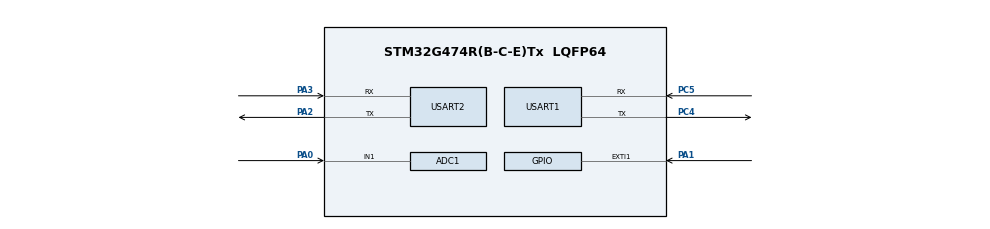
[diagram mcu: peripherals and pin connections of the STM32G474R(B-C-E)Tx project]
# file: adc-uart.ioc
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ADC1.AWD1ITMode=ENABLE
ADC1.Channel-0\#ChannelRegularConversion=ADC_CHANNEL_1
ADC1.EnableAnalogWatchDog1=true
ADC1.ExternalTrigConv=ADC_EXTERNALTRIG_T3_TRGO
ADC1.NbrOfConversionFlag=1
ADC1.OffsetNumber-0\#ChannelRegularConversion=ADC_OFFSET_NONE
ADC1.Rank-0\#ChannelRegularConversion=1
ADC1.SamplingTime-0\#ChannelRegularConversion=ADC_SAMPLETIME_2CYCLES_5
ADC1.WatchdogChannel=ADC_CHANNEL_1
ADC1.master=1
Dma.ADC1.2.Direction=DMA_PERIPH_TO_MEMORY
Dma.ADC1.2.EventEnable=DISABLE
Dma.ADC1.2.Instance=DMA1_Channel3
Dma.ADC1.2.MemDataAlignment=DMA_MDATAALIGN_HALFWORD
Dma.ADC1.2.MemInc=DMA_MINC_ENABLE
Dma.ADC1.2.Mode=DMA_NORMAL
Dma.ADC1.2.PeriphDataAlignment=DMA_PDATAALIGN_HALFWORD
Dma.ADC1.2.PeriphInc=DMA_PINC_DISABLE
Dma.ADC1.2.Polarity=HAL_DMAMUX_REQ_GEN_RISING
Dma.ADC1.2.Priority=DMA_PRIORITY_HIGH
Dma.ADC1.2.RequestNumber=1
Dma.ADC1.2.SignalID=NONE
Dma.ADC1.2.SyncEnable=DISABLE
Dma.ADC1.2.SyncPolarity=HAL_DMAMUX_SYNC_NO_EVENT
Dma.ADC1.2.SyncRequestNumber=1
Dma.ADC1.2.SyncSignalID=NONE
Dma.Request0=USART1_TX
Dma.Request1=USART2_TX
Dma.Request2=ADC1
Dma.Request3=USART1_RX
Dma.Request4=USART2_RX
Dma.USART1_RX.3.Direction=DMA_PERIPH_TO_MEMORY
Dma.USART1_RX.3.EventEnable=DISABLE
Dma.USART1_RX.3.Instance=DMA1_Channel4
Dma.USART1_RX.3.MemDataAlignment=DMA_MDATAALIGN_BYTE
Dma.USART1_RX.3.MemInc=DMA_MINC_ENABLE
Dma.USART1_RX.3.Mode=DMA_NORMAL
Dma.USART1_RX.3.PeriphDataAlignment=DMA_PDATAALIGN_BYTE
Dma.USART1_RX.3.PeriphInc=DMA_PINC_DISABLE
Dma.USART1_RX.3.Polarity=HAL_DMAMUX_REQ_GEN_RISING
Dma.USART1_RX.3.Priority=DMA_PRIORITY_LOW
Dma.USART1_RX.3.RequestNumber=1
Dma.USART1_RX.3.SignalID=NONE
Dma.USART1_RX.3.SyncEnable=DISABLE
Dma.USART1_RX.3.SyncPolarity=HAL_DMAMUX_SYNC_NO_EVENT
Dma.USART1_RX.3.SyncRequestNumber=1
Dma.USART1_RX.3.SyncSignalID=NONE
Dma.USART1_TX.0.Direction=DMA_MEMORY_TO_PERIPH
Dma.USART1_TX.0.EventEnable=DISABLE
Dma.USART1_TX.0.Instance=DMA1_Channel1
Dma.USART1_TX.0.MemDataAlignment=DMA_MDATAALIGN_BYTE
Dma.USART1_TX.0.MemInc=DMA_MINC_ENABLE
Dma.USART1_TX.0.Mode=DMA_NORMAL
Dma.USART1_TX.0.PeriphDataAlignment=DMA_PDATAALIGN_BYTE
Dma.USART1_TX.0.PeriphInc=DMA_PINC_DISABLE
Dma.USART1_TX.0.Polarity=HAL_DMAMUX_REQ_GEN_RISING
Dma.USART1_TX.0.Priority=DMA_PRIORITY_LOW
Dma.USART1_TX.0.RequestNumber=1
Dma.USART1_TX.0.SignalID=NONE
Dma.USART1_TX.0.SyncEnable=DISABLE
Dma.USART1_TX.0.SyncPolarity=HAL_DMAMUX_SYNC_NO_EVENT
Dma.USART1_TX.0.SyncRequestNumber=1
Dma.USART1_TX.0.SyncSignalID=NONE
Dma.USART2_RX.4.Direction=DMA_PERIPH_TO_MEMORY
Dma.USART2_RX.4.EventEnable=DISABLE
Dma.USART2_RX.4.Instance=DMA1_Channel5
Dma.USART2_RX.4.MemDataAlignment=DMA_MDATAALIGN_BYTE
Dma.USART2_RX.4.MemInc=DMA_MINC_ENABLE
Dma.USART2_RX.4.Mode=DMA_NORMAL
Dma.USART2_RX.4.PeriphDataAlignment=DMA_PDATAALIGN_BYTE
Dma.USART2_RX.4.PeriphInc=DMA_PINC_DISABLE
Dma.USART2_RX.4.Polarity=HAL_DMAMUX_REQ_GEN_RISING
Dma.USART2_RX.4.Priority=DMA_PRIORITY_LOW
Dma.USART2_RX.4.RequestNumber=1
Dma.USART2_RX.4.SignalID=NONE
Dma.USART2_RX.4.SyncEnable=DISABLE
Dma.USART2_RX.4.SyncPolarity=HAL_DMAMUX_SYNC_NO_EVENT
Dma.USART2_RX.4.SyncRequestNumber=1
Dma.USART2_RX.4.SyncSignalID=NONE
Dma.USART2_TX.1.Direction=DMA_MEMORY_TO_PERIPH
Dma.USART2_TX.1.EventEnable=DISABLE
Dma.USART2_TX.1.Instance=DMA1_Channel2
Dma.USART2_TX.1.MemDataAlignment=DMA_MDATAALIGN_BYTE
Dma.USART2_TX.1.MemInc=DMA_MINC_ENABLE
Dma.USART2_TX.1.Mode=DMA_NORMAL
Dma.USART2_TX.1.PeriphDataAlignment=DMA_PDATAALIGN_BYTE
Dma.USART2_TX.1.PeriphInc=DMA_PINC_DISABLE
Dma.USART2_TX.1.Polarity=HAL_DMAMUX_REQ_GEN_RISING
Dma.USART2_TX.1.Priority=DMA_PRIORITY_LOW
Dma.USART2_TX.1.RequestNumber=1
Dma.USART2_TX.1.SignalID=NONE
Dma.USART2_TX.1.SyncEnable=DISABLE
Dma.USART2_TX.1.SyncPolarity=HAL_DMAMUX_SYNC_NO_EVENT
Dma.USART2_TX.1.SyncRequestNumber=1
Dma.USART2_TX.1.SyncSignalID=NONE
Mcu.Family=STM32G4
Mcu.Name=STM32G474R(B-C-E)Tx
Mcu.Package=LQFP64
NVIC.ADC1_2_IRQn=true\:0\:0\:false\:false\:true\:true\:true\:true
NVIC.DMA1_Channel1_IRQn=true\:0\:0\:false\:false\:true\:false\:true\:true
NVIC.DMA1_Channel2_IRQn=true\:0\:0\:false\:false\:true\:false\:true\:true
NVIC.DMA1_Channel3_IRQn=true\:0\:0\:false\:false\:true\:false\:true\:true
NVIC.DMA1_Channel4_IRQn=true\:0\:0\:false\:false\:true\:false\:true\:true
NVIC.DMA1_Channel5_IRQn=true\:0\:0\:false\:false\:true\:false\:true\:true
NVIC.EXTI1_IRQn=true\:0\:0\:false\:false\:true\:true\:true\:true
NVIC.PriorityGroup=NVIC_PRIORITYGROUP_4
NVIC.TIM2_IRQn=true\:0\:0\:false\:false\:true\:true\:true\:true
NVIC.TIM3_IRQn=true\:0\:0\:false\:false\:true\:true\:true\:true
NVIC.USART1_IRQn=true\:0\:0\:false\:false\:true\:true\:true\:true
NVIC.USART2_IRQn=true\:0\:0\:false\:false\:true\:true\:true\:true
PA0.Mode=IN1-Single-Ended
PA0.Signal=ADC1_IN1
PA1.Signal=GPXTI1
PA2.Mode=Asynchronous
PA2.Signal=USART2_TX
PA3.Mode=Asynchronous
PA3.Signal=USART2_RX
PC4.Mode=Asynchronous
PC4.Signal=USART1_TX
PC5.Mode=Asynchronous
PC5.Signal=USART1_RX
ProjectManager.HeapSize=0x200
ProjectManager.StackSize=0x400
ProjectManager.TargetToolchain=STM32CubeIDE
RCC.ADC12Freq_Value=170000000
RCC.ADC345Freq_Value=170000000
RCC.AHBFreq_Value=170000000
RCC.APB1Freq_Value=170000000
RCC.APB1TimFreq_Value=170000000
RCC.APB2Freq_Value=170000000
RCC.APB2TimFreq_Value=170000000
RCC.CortexFreq_Value=170000000
RCC.EXTERNAL_CLOCK_VALUE=12288000
RCC.HCLKFreq_Value=170000000
RCC.HSE_VALUE=24000000
RCC.HSI48_VALUE=48000000
RCC.HSI_VALUE=16000000
RCC.LSE_VALUE=32768
RCC.PLLM=RCC_PLLM_DIV4
RCC.PLLN=85
RCC.RTCClockSelection=RCC_RTCCLKSOURCE_LSE
RCC.SYSCLKFreq_VALUE=170000000
RCC.SYSCLKSource=RCC_SYSCLKSOURCE_PLLCLK
RCC.USBFreq_Value=170000000
RCC.VCOOutputFreq_Value=340000000
TIM2.PeriodNoDither=9
TIM2.Prescaler=169
TIM3.PeriodNoDither=99
TIM3.Prescaler=169
TIM3.TIM_MasterOutputTrigger=TIM_TRGO_UPDATE
USART1.Parity=PARITY_EVEN
USART1.VirtualMode-Asynchronous=VM_ASYNC
USART1.WordLength=WORDLENGTH_9B
USART2.Parity=PARITY_EVEN
USART2.VirtualMode-Asynchronous=VM_ASYNC
USART2.WordLength=WORDLENGTH_9B
VP_SYS_VS_DBSignals.Mode=DisableDeadBatterySignals
VP_TIM2_VS_ClockSourceINT.Mode=Internal
VP_TIM3_VS_ClockSourceINT.Mode=Internal
board=NUCLEO-G474RE

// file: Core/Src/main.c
/* USER CODE BEGIN Header */
/**
  ******************************************************************************
  * @file           : main.c
  * @brief          : Main program body
  ******************************************************************************
  * @attention
  *
  * Copyright (c) 2025 STMicroelectronics.
  * All rights reserved.
  *
  * This software is licensed under terms that can be found in the LICENSE file
  * in the root directory of this software component.
  * If no LICENSE file comes with this software, it is provided AS-IS.
  *
  ******************************************************************************
  */
/* USER CODE END Header */
#include "main.h"
#include "common.h"

ADC_HandleTypeDef hadc1;
DMA_HandleTypeDef hdma_adc1;

TIM_HandleTypeDef htim2;
TIM_HandleTypeDef htim3;

UART_HandleTypeDef huart1;
UART_HandleTypeDef huart2;
DMA_HandleTypeDef hdma_usart1_tx;
DMA_HandleTypeDef hdma_usart1_rx;
DMA_HandleTypeDef hdma_usart2_tx;
DMA_HandleTypeDef hdma_usart2_rx;

void SystemClock_Config(void);
static void MX_GPIO_Init(void);
static void MX_DMA_Init(void);
static void MX_ADC1_Init(void);
static void MX_TIM3_Init(void);
static void MX_USART1_UART_Init(void);
static void MX_USART2_UART_Init(void);
static void MX_TIM2_Init(void);

int main(void)
{

  /* MCU Configuration--------------------------------------------------------*/

  /* Reset of all peripherals, Initializes the Flash interface and the Systick. */
  HAL_Init();

  /* Configure the system clock */
  SystemClock_Config();

  /* Initialize all configured peripherals */
  MX_GPIO_Init();
  MX_DMA_Init();
  MX_ADC1_Init();
  MX_TIM3_Init();
  MX_USART1_UART_Init();
  MX_USART2_UART_Init();
  MX_TIM2_Init();
  uint32_t clk = SystemCoreClock;
  /* USER CODE BEGIN 2 */
  //Print("****************************************************************\r\n");
 // Print("                     SYSTEM START\r\n");
  //Print("****************************************************************\r\n");
  //Print("ADC Calibration\r\n");
  if (HAL_ADCEx_Calibration_Start(&hadc1,ADC_SINGLE_ENDED) != HAL_OK) {
    // Calibration Error
    Error_Handler();
  }
  HAL_UART_Receive_DMA(ACTIVE_UART, uart_rx_buffer, CMD_STR_LEN);

  /* USER CODE END 2 */

  /* Infinite loop */
  while (1)
  {

  }
}

void SystemClock_Config(void)
{
  RCC_OscInitTypeDef RCC_OscInitStruct = {0};
  RCC_ClkInitTypeDef RCC_ClkInitStruct = {0};

  /** Configure the main internal regulator output voltage
  */
  HAL_PWREx_ControlVoltageScaling(PWR_REGULATOR_VOLTAGE_SCALE1_BOOST);

  /** Initializes the RCC Oscillators according to the specified parameters
  * in the RCC_OscInitTypeDef structure.
  */
  RCC_OscInitStruct.OscillatorType = RCC_OSCILLATORTYPE_HSI;
  RCC_OscInitStruct.HSIState = RCC_HSI_ON;
  RCC_OscInitStruct.HSICalibrationValue = RCC_HSICALIBRATION_DEFAULT;
  RCC_OscInitStruct.PLL.PLLState = RCC_PLL_ON;
  RCC_OscInitStruct.PLL.PLLSource = RCC_PLLSOURCE_HSI;
  RCC_OscInitStruct.PLL.PLLM = RCC_PLLM_DIV4;
  RCC_OscInitStruct.PLL.PLLN = 170;
  RCC_OscInitStruct.PLL.PLLP = RCC_PLLP_DIV2;
  RCC_OscInitStruct.PLL.PLLQ = RCC_PLLQ_DIV2;
  RCC_OscInitStruct.PLL.PLLR = RCC_PLLR_DIV2;
  if (HAL_RCC_OscConfig(&RCC_OscInitStruct) != HAL_OK)
  {
    Error_Handler();
  }

  /** Initializes the CPU, AHB and APB buses clocks
  */
  RCC_ClkInitStruct.ClockType = RCC_CLOCKTYPE_HCLK|RCC_CLOCKTYPE_SYSCLK
                              |RCC_CLOCKTYPE_PCLK1|RCC_CLOCKTYPE_PCLK2;
  RCC_ClkInitStruct.SYSCLKSource = RCC_SYSCLKSOURCE_PLLCLK;
  RCC_ClkInitStruct.AHBCLKDivider = RCC_SYSCLK_DIV1;
  RCC_ClkInitStruct.APB1CLKDivider = RCC_HCLK_DIV1;
  RCC_ClkInitStruct.APB2CLKDivider = RCC_HCLK_DIV1;

  if (HAL_RCC_ClockConfig(&RCC_ClkInitStruct, FLASH_LATENCY_4) != HAL_OK)
  {
    Error_Handler();
  }
}

static void MX_ADC1_Init(void)
{

  ADC_MultiModeTypeDef multimode = {0};
  ADC_ChannelConfTypeDef sConfig = {0};

  /** Common config
  */
  hadc1.Instance = ADC1;
  hadc1.Init.ClockPrescaler = ADC_CLOCK_SYNC_PCLK_DIV4;
  hadc1.Init.Resolution = ADC_RESOLUTION_12B;
  hadc1.Init.DataAlign = ADC_DATAALIGN_RIGHT;
  hadc1.Init.GainCompensation = 0;
  hadc1.Init.ScanConvMode = ADC_SCAN_DISABLE;
  hadc1.Init.EOCSelection = ADC_EOC_SINGLE_CONV;
  hadc1.Init.LowPowerAutoWait = DISABLE;
  hadc1.Init.ContinuousConvMode = DISABLE;
  hadc1.Init.NbrOfConversion = 1;
  hadc1.Init.DiscontinuousConvMode = DISABLE;
  hadc1.Init.ExternalTrigConv = ADC_EXTERNALTRIG_T3_TRGO;
  hadc1.Init.ExternalTrigConvEdge = ADC_EXTERNALTRIGCONVEDGE_RISING;
  hadc1.Init.DMAContinuousRequests = ENABLE;
  hadc1.Init.Overrun = ADC_OVR_DATA_PRESERVED;
  hadc1.Init.OversamplingMode = DISABLE;
  if (HAL_ADC_Init(&hadc1) != HAL_OK)
  {
    Error_Handler();
  }

  /** Configure the ADC multi-mode
  */
  multimode.Mode = ADC_MODE_INDEPENDENT;
  if (HAL_ADCEx_MultiModeConfigChannel(&hadc1, &multimode) != HAL_OK)
  {
    Error_Handler();
  }

  /** Configure Regular Channel
  */
  sConfig.Channel = ADC_CHANNEL_1;
  sConfig.Rank = ADC_REGULAR_RANK_1;
  sConfig.SamplingTime = ADC_SAMPLETIME_12CYCLES_5;
  sConfig.SingleDiff = ADC_SINGLE_ENDED;
  sConfig.OffsetNumber = ADC_OFFSET_NONE;
  sConfig.Offset = 0;
  if (HAL_ADC_ConfigChannel(&hadc1, &sConfig) != HAL_OK)
  {
    Error_Handler();
  }

}

static void MX_TIM2_Init(void)
{

  TIM_ClockConfigTypeDef sClockSourceConfig = {0};
  TIM_MasterConfigTypeDef sMasterConfig = {0};

  htim2.Instance = TIM2;
  htim2.Init.Prescaler = 169;
  htim2.Init.CounterMode = TIM_COUNTERMODE_UP;
  htim2.Init.Period = 0xFFFFFFFF;
  htim2.Init.ClockDivision = TIM_CLOCKDIVISION_DIV1;
  htim2.Init.AutoReloadPreload = TIM_AUTORELOAD_PRELOAD_DISABLE;
  if (HAL_TIM_Base_Init(&htim2) != HAL_OK)
  {
    Error_Handler();
  }
  sClockSourceConfig.ClockSource = TIM_CLOCKSOURCE_INTERNAL;
  if (HAL_TIM_ConfigClockSource(&htim2, &sClockSourceConfig) != HAL_OK)
  {
    Error_Handler();
  }
  sMasterConfig.MasterOutputTrigger = TIM_TRGO_RESET;
  sMasterConfig.MasterSlaveMode = TIM_MASTERSLAVEMODE_DISABLE;
  if (HAL_TIMEx_MasterConfigSynchronization(&htim2, &sMasterConfig) != HAL_OK)
  {
    Error_Handler();
  }

}

static void MX_TIM3_Init(void)
{

  TIM_ClockConfigTypeDef sClockSourceConfig = {0};
  TIM_MasterConfigTypeDef sMasterConfig = {0};

  htim3.Instance = TIM3;
  htim3.Init.Prescaler = 169;
  htim3.Init.CounterMode = TIM_COUNTERMODE_UP;
  htim3.Init.Period = 199;
  htim3.Init.ClockDivision = TIM_CLOCKDIVISION_DIV1;
  htim3.Init.AutoReloadPreload = TIM_AUTORELOAD_PRELOAD_DISABLE;
  if (HAL_TIM_Base_Init(&htim3) != HAL_OK)
  {
    Error_Handler();
  }
  sClockSourceConfig.ClockSource = TIM_CLOCKSOURCE_INTERNAL;
  if (HAL_TIM_ConfigClockSource(&htim3, &sClockSourceConfig) != HAL_OK)
  {
    Error_Handler();
  }
  sMasterConfig.MasterOutputTrigger = TIM_TRGO_UPDATE;
  sMasterConfig.MasterSlaveMode = TIM_MASTERSLAVEMODE_DISABLE;
  if (HAL_TIMEx_MasterConfigSynchronization(&htim3, &sMasterConfig) != HAL_OK)
  {
    Error_Handler();
  }

}

static void MX_USART1_UART_Init(void)
{

  huart1.Instance = USART1;
  huart1.Init.BaudRate = 115200;
  huart1.Init.WordLength = UART_WORDLENGTH_9B;
  huart1.Init.StopBits = UART_STOPBITS_1;
  huart1.Init.Parity = UART_PARITY_EVEN;
  huart1.Init.Mode = UART_MODE_TX_RX;
  huart1.Init.HwFlowCtl = UART_HWCONTROL_NONE;
  huart1.Init.OverSampling = UART_OVERSAMPLING_16;
  huart1.Init.OneBitSampling = UART_ONE_BIT_SAMPLE_DISABLE;
  huart1.Init.ClockPrescaler = UART_PRESCALER_DIV1;
  huart1.AdvancedInit.AdvFeatureInit = UART_ADVFEATURE_NO_INIT;
  if (HAL_UART_Init(&huart1) != HAL_OK)
  {
    Error_Handler();
  }
  if (HAL_UARTEx_SetTxFifoThreshold(&huart1, UART_TXFIFO_THRESHOLD_1_8) != HAL_OK)
  {
    Error_Handler();
  }
  if (HAL_UARTEx_SetRxFifoThreshold(&huart1, UART_RXFIFO_THRESHOLD_1_8) != HAL_OK)
  {
    Error_Handler();
  }
  if (HAL_UARTEx_DisableFifoMode(&huart1) != HAL_OK)
  {
    Error_Handler();
  }

}

static void MX_USART2_UART_Init(void)
{

  huart2.Instance = USART2;
  huart2.Init.BaudRate = 115200;
  huart2.Init.WordLength = UART_WORDLENGTH_9B;
  huart2.Init.StopBits = UART_STOPBITS_1;
  huart2.Init.Parity = UART_PARITY_EVEN;
  huart2.Init.Mode = UART_MODE_TX_RX;
  huart2.Init.HwFlowCtl = UART_HWCONTROL_NONE;
  huart2.Init.OverSampling = UART_OVERSAMPLING_16;
  huart2.Init.OneBitSampling = UART_ONE_BIT_SAMPLE_DISABLE;
  huart2.Init.ClockPrescaler = UART_PRESCALER_DIV1;
  huart2.AdvancedInit.AdvFeatureInit = UART_ADVFEATURE_NO_INIT;
  if (HAL_UART_Init(&huart2) != HAL_OK)
  {
    Error_Handler();
  }
  if (HAL_UARTEx_SetTxFifoThreshold(&huart2, UART_TXFIFO_THRESHOLD_1_8) != HAL_OK)
  {
    Error_Handler();
  }
  if (HAL_UARTEx_SetRxFifoThreshold(&huart2, UART_RXFIFO_THRESHOLD_1_8) != HAL_OK)
  {
    Error_Handler();
  }
  if (HAL_UARTEx_DisableFifoMode(&huart2) != HAL_OK)
  {
    Error_Handler();
  }

}

static void MX_DMA_Init(void)
{

  /* DMA controller clock enable */
  __HAL_RCC_DMAMUX1_CLK_ENABLE();
  __HAL_RCC_DMA1_CLK_ENABLE();

  /* DMA interrupt init */
  /* DMA1_Channel1_IRQn interrupt configuration */
  HAL_NVIC_SetPriority(DMA1_Channel1_IRQn, 0, 0);
  HAL_NVIC_EnableIRQ(DMA1_Channel1_IRQn);
  /* DMA1_Channel2_IRQn interrupt configuration */
  HAL_NVIC_SetPriority(DMA1_Channel2_IRQn, 0, 0);
  HAL_NVIC_EnableIRQ(DMA1_Channel2_IRQn);
  /* DMA1_Channel3_IRQn interrupt configuration */
  HAL_NVIC_SetPriority(DMA1_Channel3_IRQn, 0, 0);
  HAL_NVIC_EnableIRQ(DMA1_Channel3_IRQn);
  /* DMA1_Channel4_IRQn interrupt configuration */
  HAL_NVIC_SetPriority(DMA1_Channel4_IRQn, 0, 0);
  HAL_NVIC_EnableIRQ(DMA1_Channel4_IRQn);
  /* DMA1_Channel5_IRQn interrupt configuration */
  HAL_NVIC_SetPriority(DMA1_Channel5_IRQn, 0, 0);
  HAL_NVIC_EnableIRQ(DMA1_Channel5_IRQn);

}

static void MX_GPIO_Init(void)
{
  GPIO_InitTypeDef GPIO_InitStruct = {0};

  /* GPIO Ports Clock Enable */
  __HAL_RCC_GPIOA_CLK_ENABLE();
  __HAL_RCC_GPIOC_CLK_ENABLE();

  /*Configure GPIO pin : PA1 */
  GPIO_InitStruct.Pin = GPIO_PIN_1;
  GPIO_InitStruct.Mode = GPIO_MODE_IT_RISING_FALLING;
  GPIO_InitStruct.Pull = GPIO_PULLDOWN;
  HAL_GPIO_Init(GPIOA, &GPIO_InitStruct);

  /* EXTI interrupt init*/
  HAL_NVIC_SetPriority(EXTI1_IRQn, 5, 0);
  HAL_NVIC_EnableIRQ(EXTI1_IRQn);

}

void Error_Handler(void)
{
  __disable_irq();
  while (1)
  {
  }
}
